VERSION 5.4 ;
NAMESCASESENSITIVE ON ;
BUSBITCHARS "[]" ;
DIVIDERCHAR "/" ;
UNITS
  DATABASE MICRONS 2000 ;
END UNITS
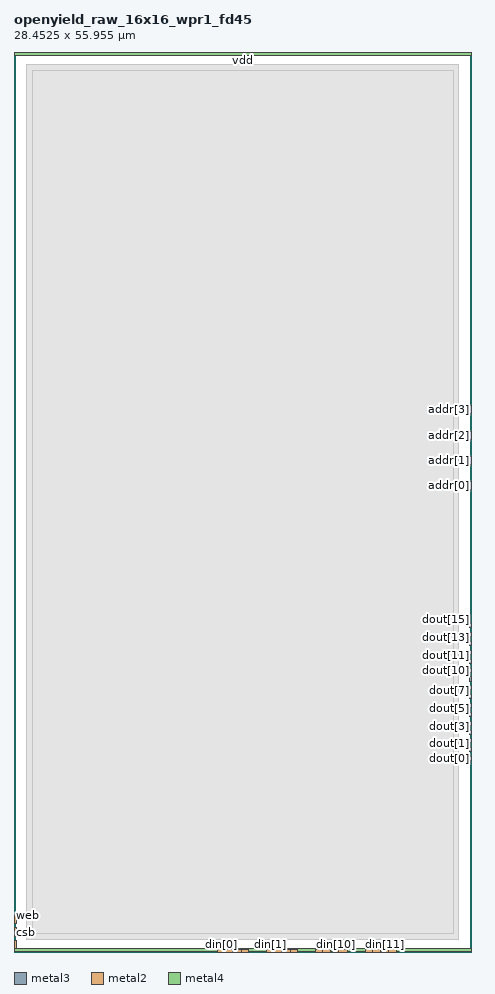
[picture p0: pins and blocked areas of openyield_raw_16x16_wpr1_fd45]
MACRO openyield_raw_16x16_wpr1_fd45
   CLASS BLOCK ;
   SIZE 28.4525 BY 55.9550 ;
   SYMMETRY X Y R90 ;
   PIN addr[0]
      DIRECTION INPUT ;
      PORT
         LAYER metal3 ;
         RECT 28.2925 28.7575 28.4525 29.2575 ;
      END
   END addr[0]
   PIN addr[1]
      DIRECTION INPUT ;
      PORT
         LAYER metal3 ;
         RECT 28.2925 30.3225 28.4525 30.8225 ;
      END
   END addr[1]
   PIN addr[2]
      DIRECTION INPUT ;
      PORT
         LAYER metal3 ;
         RECT 28.2925 31.8875 28.4525 32.3875 ;
      END
   END addr[2]
   PIN addr[3]
      DIRECTION INPUT ;
      PORT
         LAYER metal3 ;
         RECT 28.2925 33.4525 28.4525 33.9525 ;
      END
   END addr[3]
   PIN clk
      DIRECTION INPUT ;
      PORT
         LAYER metal2 ;
         RECT 0.0000 0.2425 0.1600 0.7425 ;
      END
   END clk
   PIN csb
      DIRECTION INPUT ;
      PORT
         LAYER metal2 ;
         RECT 0.0000 0.9925 0.1600 1.4925 ;
      END
   END csb
   PIN din[0]
      DIRECTION INPUT ;
      PORT
         LAYER metal2 ;
         RECT 12.6550 0.0000 13.1550 0.1600 ;
      END
   END din[0]
   PIN din[10]
      DIRECTION INPUT ;
      PORT
         LAYER metal2 ;
         RECT 19.7760 0.0000 20.2760 0.1600 ;
      END
   END din[10]
   PIN din[11]
      DIRECTION INPUT ;
      PORT
         LAYER metal2 ;
         RECT 22.8360 0.0000 23.3360 0.1600 ;
      END
   END din[11]
   PIN din[12]
      DIRECTION INPUT ;
      PORT
         LAYER metal2 ;
         RECT 14.0850 0.0000 14.5850 0.1600 ;
      END
   END din[12]
   PIN din[13]
      DIRECTION INPUT ;
      PORT
         LAYER metal2 ;
         RECT 17.1450 0.0000 17.6450 0.1600 ;
      END
   END din[13]
   PIN din[14]
      DIRECTION INPUT ;
      PORT
         LAYER metal2 ;
         RECT 20.2050 0.0000 20.7050 0.1600 ;
      END
   END din[14]
   PIN din[15]
      DIRECTION INPUT ;
      PORT
         LAYER metal2 ;
         RECT 23.2650 0.0000 23.7650 0.1600 ;
      END
   END din[15]
   PIN din[1]
      DIRECTION INPUT ;
      PORT
         LAYER metal2 ;
         RECT 15.7150 0.0000 16.2150 0.1600 ;
      END
   END din[1]
   PIN din[2]
      DIRECTION INPUT ;
      PORT
         LAYER metal2 ;
         RECT 18.7750 0.0000 19.2750 0.1600 ;
      END
   END din[2]
   PIN din[3]
      DIRECTION INPUT ;
      PORT
         LAYER metal2 ;
         RECT 21.8350 0.0000 22.3350 0.1600 ;
      END
   END din[3]
   PIN din[4]
      DIRECTION INPUT ;
      PORT
         LAYER metal2 ;
         RECT 13.0840 0.0000 13.5840 0.1600 ;
      END
   END din[4]
   PIN din[5]
      DIRECTION INPUT ;
      PORT
         LAYER metal2 ;
         RECT 16.1440 0.0000 16.6440 0.1600 ;
      END
   END din[5]
   PIN din[6]
      DIRECTION INPUT ;
      PORT
         LAYER metal2 ;
         RECT 19.2040 0.0000 19.7040 0.1600 ;
      END
   END din[6]
   PIN din[7]
      DIRECTION INPUT ;
      PORT
         LAYER metal2 ;
         RECT 22.2640 0.0000 22.7640 0.1600 ;
      END
   END din[7]
   PIN din[8]
      DIRECTION INPUT ;
      PORT
         LAYER metal2 ;
         RECT 13.6560 0.0000 14.1560 0.1600 ;
      END
   END din[8]
   PIN din[9]
      DIRECTION INPUT ;
      PORT
         LAYER metal2 ;
         RECT 16.7160 0.0000 17.2160 0.1600 ;
      END
   END din[9]
   PIN dout[0]
      DIRECTION OUTPUT ;
      PORT
         LAYER metal3 ;
         RECT 28.2925 11.8975 28.4525 12.1475 ;
      END
   END dout[0]
   PIN dout[10]
      DIRECTION OUTPUT ;
      PORT
         LAYER metal3 ;
         RECT 28.2925 17.3975 28.4525 17.6475 ;
      END
   END dout[10]
   PIN dout[11]
      DIRECTION OUTPUT ;
      PORT
         LAYER metal3 ;
         RECT 28.2925 17.9475 28.4525 18.1975 ;
      END
   END dout[11]
   PIN dout[12]
      DIRECTION OUTPUT ;
      PORT
         LAYER metal3 ;
         RECT 28.2925 18.4975 28.4525 18.7475 ;
      END
   END dout[12]
   PIN dout[13]
      DIRECTION OUTPUT ;
      PORT
         LAYER metal3 ;
         RECT 28.2925 19.0475 28.4525 19.2975 ;
      END
   END dout[13]
   PIN dout[14]
      DIRECTION OUTPUT ;
      PORT
         LAYER metal3 ;
         RECT 28.2925 19.5975 28.4525 19.8475 ;
      END
   END dout[14]
   PIN dout[15]
      DIRECTION OUTPUT ;
      PORT
         LAYER metal3 ;
         RECT 28.2925 20.1475 28.4525 20.3975 ;
      END
   END dout[15]
   PIN dout[1]
      DIRECTION OUTPUT ;
      PORT
         LAYER metal3 ;
         RECT 28.2925 12.4475 28.4525 12.6975 ;
      END
   END dout[1]
   PIN dout[2]
      DIRECTION OUTPUT ;
      PORT
         LAYER metal3 ;
         RECT 28.2925 12.9975 28.4525 13.2475 ;
      END
   END dout[2]
   PIN dout[3]
      DIRECTION OUTPUT ;
      PORT
         LAYER metal3 ;
         RECT 28.2925 13.5475 28.4525 13.7975 ;
      END
   END dout[3]
   PIN dout[4]
      DIRECTION OUTPUT ;
      PORT
         LAYER metal3 ;
         RECT 28.2925 14.0975 28.4525 14.3475 ;
      END
   END dout[4]
   PIN dout[5]
      DIRECTION OUTPUT ;
      PORT
         LAYER metal3 ;
         RECT 28.2925 14.6475 28.4525 14.8975 ;
      END
   END dout[5]
   PIN dout[6]
      DIRECTION OUTPUT ;
      PORT
         LAYER metal3 ;
         RECT 28.2925 15.1975 28.4525 15.4475 ;
      END
   END dout[6]
   PIN dout[7]
      DIRECTION OUTPUT ;
      PORT
         LAYER metal3 ;
         RECT 28.2925 15.7475 28.4525 15.9975 ;
      END
   END dout[7]
   PIN dout[8]
      DIRECTION OUTPUT ;
      PORT
         LAYER metal3 ;
         RECT 28.2925 16.2975 28.4525 16.5475 ;
      END
   END dout[8]
   PIN dout[9]
      DIRECTION OUTPUT ;
      PORT
         LAYER metal3 ;
         RECT 28.2925 16.8475 28.4525 17.0975 ;
      END
   END dout[9]
   PIN gnd
      DIRECTION INOUT ;
      USE GROUND ;
      SHAPE ABUTMENT ;
      PORT
         LAYER metal4 ;
         RECT 0.0000 0.0500 28.4525 0.2000 ;
      END
   END gnd
   PIN vdd
      DIRECTION INOUT ;
      USE POWER ;
      SHAPE ABUTMENT ;
      PORT
         LAYER metal4 ;
         RECT 0.0000 55.7550 28.4525 55.9050 ;
      END
   END vdd
   PIN web
      DIRECTION INPUT ;
      PORT
         LAYER metal2 ;
         RECT 0.0000 1.7425 0.1600 2.2425 ;
      END
   END web
   OBS
      LAYER metal1 ;
         RECT 0.8000 0.8000 27.6525 55.1550 ;
      LAYER metal2 ;
         RECT 0.8000 0.8000 27.6525 55.1550 ;
      LAYER metal3 ;
         RECT 0.8000 0.8000 27.6525 55.1550 ;
      LAYER metal4 ;
         RECT 1.1200 1.1200 27.3325 54.8350 ;
   END
END openyield_raw_16x16_wpr1_fd45
END LIBRARY
